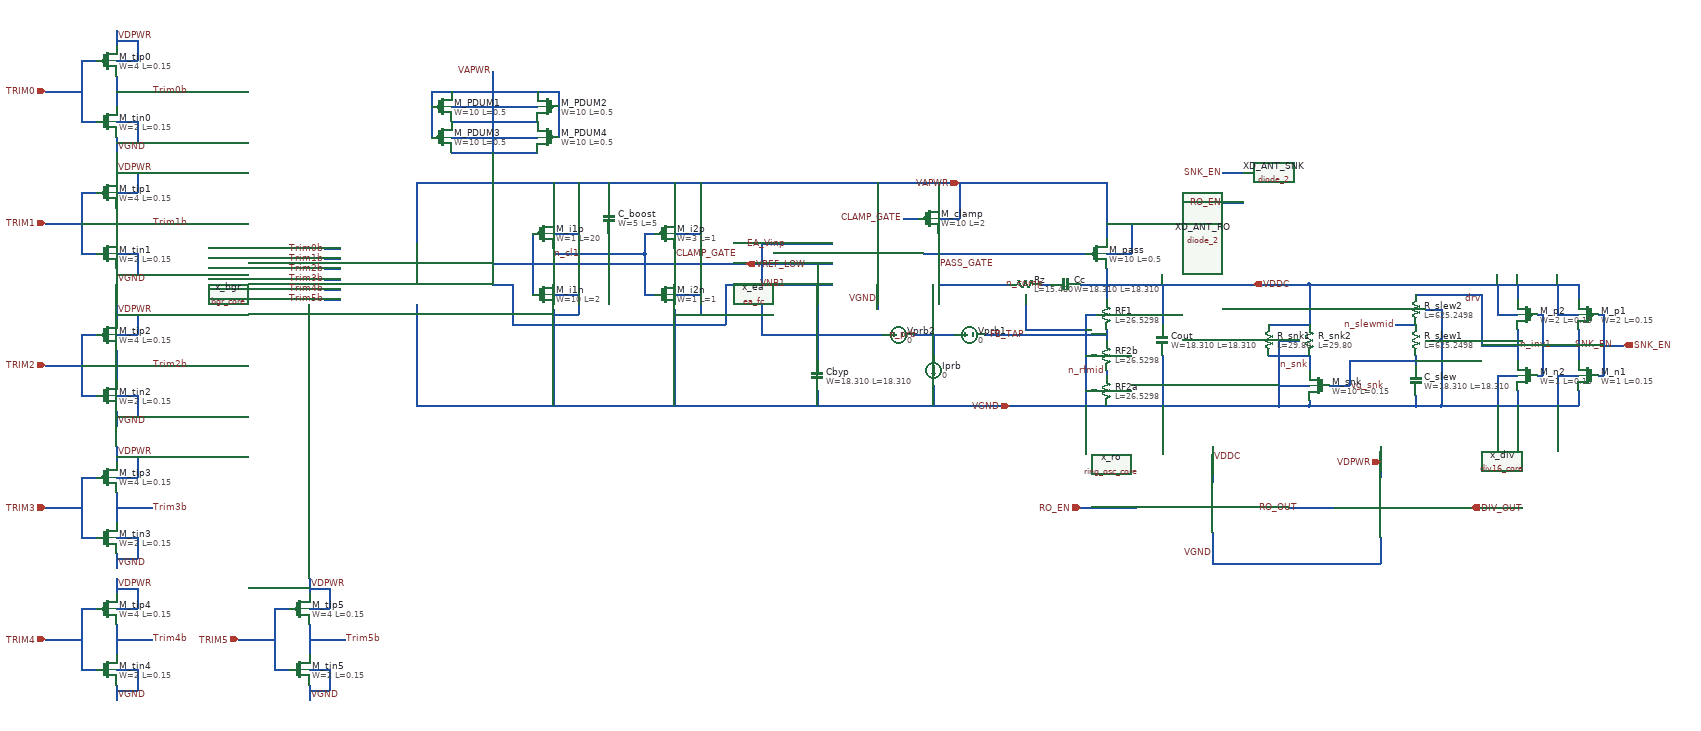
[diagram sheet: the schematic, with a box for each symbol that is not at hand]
v {xschem version=3.4.8RC file_version=1.3}
G {}
K {}
V {}
S {}
F {}
E {}
N 800 430 800 490 {lab=VGND}
N 950 380 1020 380 {lab=RO_OUT}
N 1020 380 1040 380 {lab=RO_OUT}
N 800 490 1040 490 {lab=VGND}
N -150 -260 590 -260 {lab=VAPWR}
N 590 -260 590 -150 {lab=VAPWR}
N 590 -120 640 -120 {lab=VAPWR}
N 640 -180 640 -120 {lab=VAPWR}
N 590 -180 640 -180 {lab=VAPWR}
N 590 -90 590 -30 {lab=VDDC}
N 590 180 790 180 {lab=VGND}
N 590 -60 800 -60 {lab=VDDC}
N 700 -60 700 20 {lab=VDDC}
N 700 80 700 180 {lab=VGND}
N -150 180 590 180 {lab=VGND}
N 350 -120 550 -120 {lab=PASS_GATE}
N 140 -260 140 -200 {lab=VAPWR}
N 790 180 800 180 {lab=VGND}
N 540 -60 590 -60 {lab=VDDC}
N 460 -60 480 -60 {lab=n_comp}
N 260 -60 280 -60 {lab=PASS_GATE}
N 260 -120 260 -60 {lab=PASS_GATE}
N 430 -40 430 30 {lab=VGND}
N 550 0 570 0 {lab=VGND}
N 550 0 550 110 {lab=VGND}
N 550 150 570 150 {lab=VGND}
N 550 110 550 180 {lab=VGND}
N 430 30 550 30 {lab=VGND}
N -770 -260 -770 -140 {lab=VAPWR}
N -770 -20 -770 180 {lab=VGND}
N 20 -100 20 90 {lab=VREF_LOW}
N 20 150 20 180 {lab=VGND}
N -160 -100 -120 -100 {lab=VREF_LOW}
N -160 -60 -120 -60 {lab=VNB1}
N 230 -120 350 -120 {lab=PASS_GATE}
N 280 -60 400 -60 {lab=PASS_GATE}
N -320 180 -150 180 {lab=VGND}
N -320 -260 -150 -260 {lab=VAPWR}
N -90 40 80 40 {lab=EA_Vinp}
N -120 -60 50 -60 {lab=VNB1}
N -120 -100 50 -100 {lab=VREF_LOW}
N 140 -40 140 -30 {lab=VGND}
N 990 80 990 110 {lab=n_snk}
N 990 170 990 180 {lab=VGND}
N 800 -60 990 -60 {lab=VDDC}
N 990 -60 990 20 {lab=VDDC}
N 930 50 970 50 {lab=VGND}
N 930 50 930 180 {lab=VGND}
N 930 180 990 180 {lab=VGND}
N 1030 140 1070 140 {lab=vg_snk}
N 800 180 930 180 {lab=VGND}
N 1200 80 1200 100 {lab=vg_snk}
N 1070 90 1070 140 {lab=vg_snk}
N 1070 90 1200 90 {lab=vg_snk}
N 1200 160 1200 180 {lab=VGND}
N 990 180 1200 180 {lab=VGND}
N 1220 50 1250 50 {lab=VGND}
N 1250 50 1250 180 {lab=VGND}
N 1200 180 1250 180 {lab=VGND}
N 1520 30 1520 90 {lab=n_inv1}
N 1520 150 1520 180 {lab=VGND}
N 1560 0 1570 0 {lab=SNK_EN}
N 1570 0 1570 120 {lab=SNK_EN}
N 1560 120 1570 120 {lab=SNK_EN}
N 1570 60 1610 60 {lab=SNK_EN}
N 1400 30 1400 90 {lab=drv}
N 1330 60 1400 60 {lab=drv}
N 1400 150 1400 180 {lab=VGND}
N 1250 180 1520 180 {lab=VGND}
N 1440 0 1450 0 {lab=n_inv1}
N 1450 0 1450 120 {lab=n_inv1}
N 1440 120 1450 120 {lab=n_inv1}
N 1450 60 1520 60 {lab=n_inv1}
N 1480 0 1520 0 {lab=VDDC}
N 1480 -50 1480 0 {lab=VDDC}
N 1360 0 1400 0 {lab=VDDC}
N 1360 -50 1360 0 {lab=VDDC}
N 1360 -60 1360 -50 {lab=VDDC}
N 1480 -60 1480 -50 {lab=VDDC}
N 1400 -60 1400 -30 {lab=VDDC}
N 1520 -60 1520 -30 {lab=VDDC}
N 990 -60 1520 -60 {lab=VDDC}
N 1330 -30 1330 60 {lab=drv}
N 1040 490 1130 490 {lab=VGND}
N 1130 440 1130 490 {lab=VGND}
N 800 260 800 330 {lab=VDDC}
N 1130 260 1130 320 {lab=VDPWR}
N 1220 380 1320 380 {lab=DIV_OUT}
N -90 -140 50 -140 {lab=EA_Vinp}
N -770 -260 -740 -260 {lab=VAPWR}
N -770 180 -740 180 {lab=VGND}
N 140 -30 140 -10 {lab=VGND}
N 540 380 650 380 {lab=RO_EN}
N 250 160 250 180 {lab=VGND}
N 350 40 400 40 {lab=FB_TAP}
N 930 140 990 140 {lab=VGND}
N 1360 120 1400 120 {lab=VGND}
N 1360 120 1360 180 {lab=VGND}
N 1480 120 1520 120 {lab=VGND}
N 1480 120 1480 180 {lab=VGND}
N -520 -100 -160 -100 {lab=VREF_LOW}
N -640 -260 -320 -260 {lab=VAPWR}
N -640 180 -320 180 {lab=VGND}
N -540 -160 -540 -100 {lab=VREF_LOW}
N -540 -100 -540 -40 {lab=VREF_LOW}
N -620 -60 -580 -60 {lab=VNB1}
N -580 -60 -580 20 {lab=VNB1}
N -480 20 -160 20 {lab=VNB1}
N -160 -60 -160 20 {lab=VNB1}
N -500 -260 -500 -190 {lab=VAPWR}
N -500 -160 -450 -160 {lab=VAPWR}
N -450 -260 -450 -160 {lab=VAPWR}
N -500 -130 -500 -70 {lab=n_cl1}
N -500 -10 -500 180 {lab=VGND}
N -500 -40 -450 -40 {lab=VGND}
N -450 -40 -450 0 {lab=VGND}
N -500 0 -450 0 {lab=VGND}
N -400 -120 -320 -120 {lab=n_cl1}
N -320 -160 -320 -120 {lab=n_cl1}
N -320 -160 -300 -160 {lab=n_cl1}
N -320 -120 -320 -40 {lab=n_cl1}
N -320 -40 -300 -40 {lab=n_cl1}
N -260 -10 -260 180 {lab=VGND}
N -260 0 -210 0 {lab=VGND}
N -210 -40 -210 0 {lab=VGND}
N -260 -40 -210 -40 {lab=VGND}
N -260 -130 -260 -70 {lab=CLAMP_GATE}
N -260 -260 -260 -190 {lab=VAPWR}
N -260 -160 -210 -160 {lab=VAPWR}
N -210 -260 -210 -160 {lab=VAPWR}
N 260 -160 260 -120 {lab=PASS_GATE}
N 260 -260 260 -220 {lab=VAPWR}
N 260 -190 300 -190 {lab=VAPWR}
N 300 -260 300 -190 {lab=VAPWR}
N 190 -190 220 -190 {lab=CLAMP_GATE}
N 80 40 150 40 {lab=EA_Vinp}
N 210 40 290 40 {lab=n_prb}
N 250 40 250 80 {lab=n_prb}
N -500 -120 -400 -120 {lab=n_cl1}
N -580 20 -480 20 {lab=VNB1}
N -620 -100 -520 -100 {lab=VREF_LOW}
N -740 -260 -640 -260 {lab=VAPWR}
N -740 180 -640 180 {lab=VGND}
N -390 -160 -390 -120 {lab=n_cl1}
N -390 -260 -390 -220 {lab=VAPWR}
N -1360 -470 -1360 -410 {lab=Trim0b}
N -1360 -440 -1290 -440 {lab=Trim0b}
N -1360 -350 -1360 -320 {lab=VGND}
N -1360 -500 -1320 -500 {lab=VDPWR}
N -1360 -560 -1360 -530 {lab=VDPWR}
N -1360 -380 -1320 -380 {lab=VGND}
N -1430 -500 -1400 -500 {lab=TRIM0}
N -1430 -500 -1430 -380 {lab=TRIM0}
N -1430 -380 -1400 -380 {lab=TRIM0}
N -1500 -440 -1430 -440 {lab=TRIM0}
N -1500 -180 -1430 -180 {lab=TRIM1}
N -1500 100 -1430 100 {lab=TRIM2}
N -1500 380 -1430 380 {lab=TRIM3}
N -950 -130 -920 -130 {lab=Trim0b}
N -950 -110 -920 -110 {lab=Trim1b}
N -950 -90 -920 -90 {lab=Trim2b}
N -950 -70 -920 -70 {lab=Trim3b}
N -1320 -540 -1320 -500 {lab=VDPWR}
N -1360 -540 -1320 -540 {lab=VDPWR}
N -1320 -380 -1320 -340 {lab=VGND}
N -1360 -340 -1320 -340 {lab=VGND}
N -1360 -210 -1360 -150 {lab=Trim1b}
N -1360 -90 -1360 -60 {lab=VGND}
N -1360 -240 -1320 -240 {lab=VDPWR}
N -1360 -300 -1360 -270 {lab=VDPWR}
N -1360 -120 -1320 -120 {lab=VGND}
N -1430 -240 -1400 -240 {lab=TRIM1}
N -1430 -240 -1430 -120 {lab=TRIM1}
N -1430 -120 -1400 -120 {lab=TRIM1}
N -1320 -280 -1320 -240 {lab=VDPWR}
N -1360 -280 -1320 -280 {lab=VDPWR}
N -1320 -120 -1320 -80 {lab=VGND}
N -1360 -80 -1320 -80 {lab=VGND}
N -1360 70 -1360 130 {lab=Trim2b}
N -1360 190 -1360 220 {lab=VGND}
N -1360 40 -1320 40 {lab=VDPWR}
N -1360 -20 -1360 10 {lab=VDPWR}
N -1360 160 -1320 160 {lab=VGND}
N -1430 40 -1400 40 {lab=TRIM2}
N -1430 40 -1430 160 {lab=TRIM2}
N -1430 160 -1400 160 {lab=TRIM2}
N -1320 0 -1320 40 {lab=VDPWR}
N -1360 0 -1320 0 {lab=VDPWR}
N -1320 160 -1320 200 {lab=VGND}
N -1360 200 -1320 200 {lab=VGND}
N -1360 350 -1360 410 {lab=Trim3b}
N -1360 470 -1360 500 {lab=VGND}
N -1360 320 -1320 320 {lab=VDPWR}
N -1360 260 -1360 290 {lab=VDPWR}
N -1360 440 -1320 440 {lab=VGND}
N -1430 320 -1400 320 {lab=TRIM3}
N -1430 320 -1430 440 {lab=TRIM3}
N -1430 440 -1400 440 {lab=TRIM3}
N -1320 280 -1320 320 {lab=VDPWR}
N -1360 280 -1320 280 {lab=VDPWR}
N -1320 440 -1320 480 {lab=VGND}
N -1360 480 -1320 480 {lab=VGND}
N -1360 380 -1290 380 {lab=Trim3b}
N -1360 100 -1290 100 {lab=Trim2b}
N -1360 -180 -1290 -180 {lab=Trim1b}
N 1220 -10 1250 -10 {lab=VGND}
N 1250 -10 1250 50 {lab=VGND}
N 1200 -40 1330 -40 {lab=drv}
N 1330 -40 1330 -30 {lab=drv}
N 1160 20 1200 20 {lab=n_slewmid}
N 590 110 590 120 {lab=n_rfmid}
N 550 80 570 80 {lab=VGND}
N 590 30 590 50 {lab=FB_TAP}
N 400 40 590 40 {lab=FB_TAP}
N -90 -140 -90 40 {lab=EA_Vinp}
N 250 140 250 160 {lab=VGND}
N 910 20 990 20 {lab=VDDC}
N 910 80 990 80 {lab=n_snk}
N -700 -320 -530 -320 {lab=VAPWR}
N -700 -350 -530 -350 {lab=VAPWR}
N -700 -380 -530 -380 {lab=VAPWR}
N -700 -410 -530 -410 {lab=VAPWR}
N -700 -440 -530 -440 {lab=VAPWR}
N -490 -410 -490 -350 {lab=VAPWR}
N -740 -410 -740 -350 {lab=VAPWR}
N -740 -440 -740 -410 {lab=VAPWR}
N -740 -440 -700 -440 {lab=VAPWR}
N -530 -440 -490 -440 {lab=VAPWR}
N -490 -440 -490 -410 {lab=VAPWR}
N -620 -350 -620 -320 {lab=VAPWR}
N -620 -380 -620 -350 {lab=VAPWR}
N -620 -410 -620 -380 {lab=VAPWR}
N -620 -440 -620 -410 {lab=VAPWR}
N -620 -480 -620 -440 {lab=VAPWR}
N 820 -280 860 -280 {lab=SNK_EN}
N 820 -220 860 -220 {lab=RO_EN}
N -950 -50 -920 -50 {lab=Trim5b}
N -950 -30 -920 -30 {lab=Trim5b}
N -1500 640 -1430 640 {lab=TRIM4}
N -1360 610 -1360 670 {lab=Trim4b}
N -1360 730 -1360 760 {lab=VGND}
N -1360 580 -1320 580 {lab=VDPWR}
N -1360 520 -1360 550 {lab=VDPWR}
N -1360 700 -1320 700 {lab=VGND}
N -1430 580 -1400 580 {lab=TRIM4}
N -1430 580 -1430 700 {lab=TRIM4}
N -1430 700 -1400 700 {lab=TRIM4}
N -1320 540 -1320 580 {lab=VDPWR}
N -1360 540 -1320 540 {lab=VDPWR}
N -1320 700 -1320 740 {lab=VGND}
N -1360 740 -1320 740 {lab=VGND}
N -1360 640 -1290 640 {lab=Trim4b}
N -1120 640 -1050 640 {lab=TRIM5}
N -980 610 -980 670 {lab=Trim5b}
N -980 730 -980 760 {lab=VGND}
N -980 580 -940 580 {lab=VDPWR}
N -980 520 -980 550 {lab=VDPWR}
N -980 700 -940 700 {lab=VGND}
N -1050 580 -1020 580 {lab=TRIM5}
N -1050 580 -1050 700 {lab=TRIM5}
N -1050 700 -1020 700 {lab=TRIM5}
N -940 540 -940 580 {lab=VDPWR}
N -980 540 -940 540 {lab=VDPWR}
N -940 700 -940 740 {lab=VGND}
N -980 740 -940 740 {lab=VGND}
N -980 640 -910 640 {lab=Trim5b}
C {ring_osc_core.sym} 800 380 0 0 {name=x_ro}
C {lab_pin.sym} 970 380 3 0 {name=p9 sig_type=std_logic lab=RO_OUT}
C {lab_pin.sym} 800 280 2 0 {name=p10 sig_type=std_logic lab=VDDC


}
C {pfet_g5v0d10v5.sym} 570 -120 0 0 {name=M_pass
W=10
L=0.5
nf=1
mult=40
ad="expr('int((@nf + 1)/2) * @W / @nf * 0.29')"
pd="expr('2*int((@nf + 1)/2) * (@W / @nf + 0.29)')"
as="expr('int((@nf + 2)/2) * @W / @nf * 0.29')"
ps="expr('2*int((@nf + 2)/2) * (@W / @nf + 0.29)')"
nrd="expr('0.29 / @W ')" nrs="expr('0.29 / @W ')"
sa=0 sb=0 sd=0
model=pfet_g5v0d10v5
spiceprefix=X
}
C {ea_fc.sym} 130 -120 0 0 {name=x_ea}
C {res_high_po_0p69.sym} 590 0 0 0 {name=RF1
L=26.5298
model=res_high_po_0p69
spiceprefix=X
mult=1}
C {res_high_po_0p69.sym} 590 150 0 0 {name=RF2a
L=26.5298
model=res_high_po_0p69
spiceprefix=X
mult=1}
C {res_high_po_0p69.sym} 430 -60 1 1 {name=Rz
L=15.480
model=res_high_po_0p69
spiceprefix=X
mult=1}
C {cap_mim_m3_1.sym} 700 50 0 0 {name=Cout model=cap_mim_m3_1 W=18.310 L=18.310 MF=32 spiceprefix=X}
C {cap_mim_m3_1.sym} 510 -60 3 0 {name=Cc model=cap_mim_m3_1 W=18.310 L=18.310 MF=4 spiceprefix=X}
C {bgr_core.sym} -770 -80 0 0 {name=x_bgr}
C {lab_pin.sym} -40 -60 3 0 {name=p4 sig_type=std_logic lab=VNB1


}
C {cap_mim_m3_1.sym} 20 120 0 0 {name=Cbyp model=cap_mim_m3_1 W=18.310 L=18.310 MF=3 spiceprefix=X}
C {res_high_po_0p69.sym} 1200 -10 0 1 {name=R_slew2
L=625.2498
model=res_high_po_0p69
spiceprefix=X
mult=1}
C {cap_mim_m3_1.sym} 1200 130 0 0 {name=C_slew model=cap_mim_m3_1 W=18.310 L=18.310 MF=2 spiceprefix=X}
C {lab_pin.sym} 1070 140 2 0 {name=p2 sig_type=std_logic lab=vg_snk


}
C {lab_pin.sym} 1330 -30 2 1 {name=p3 sig_type=std_logic lab=drv


}
C {pfet_01v8.sym} 1540 0 0 1 {name=M_p1
W=2
L=0.15
nf=1
mult=1
ad="expr('int((@nf + 1)/2) * @W / @nf * 0.29')"
pd="expr('2*int((@nf + 1)/2) * (@W / @nf + 0.29)')"
as="expr('int((@nf + 2)/2) * @W / @nf * 0.29')"
ps="expr('2*int((@nf + 2)/2) * (@W / @nf + 0.29)')"
nrd="expr('0.29 / @W ')" nrs="expr('0.29 / @W ')"
sa=0 sb=0 sd=0
model=pfet_01v8
spiceprefix=X
}
C {pfet_01v8.sym} 1420 0 0 1 {name=M_p2
W=2
L=0.15
nf=1
mult=1
ad="expr('int((@nf + 1)/2) * @W / @nf * 0.29')"
pd="expr('2*int((@nf + 1)/2) * (@W / @nf + 0.29)')"
as="expr('int((@nf + 2)/2) * @W / @nf * 0.29')"
ps="expr('2*int((@nf + 2)/2) * (@W / @nf + 0.29)')"
nrd="expr('0.29 / @W ')" nrs="expr('0.29 / @W ')"
sa=0 sb=0 sd=0
model=pfet_01v8
spiceprefix=X
}
C {lab_pin.sym} 1590 60 1 1 {name=p5 sig_type=std_logic lab=SNK_EN


}
C {lab_pin.sym} 1470 60 1 1 {name=p6 sig_type=std_logic lab=n_inv1


}
C {res_high_po_5p73.sym} 990 50 0 0 {name=R_snk2
L=29.80
model=res_high_po_5p73
spiceprefix=X
mult=1}
C {div16_core.sym} 1130 380 0 0 {name=x_div}
C {ipin.sym} 1610 60 0 1 {name=p13 lab=SNK_EN}
C {ipin.sym} -1500 -440 0 0 {name=p14 lab=TRIM0}
C {ipin.sym} -1500 -180 0 0 {name=p16 lab=TRIM1}
C {ipin.sym} -1500 100 0 0 {name=p17 lab=TRIM2}
C {ipin.sym} -1500 380 0 0 {name=p18 lab=TRIM3}
C {lab_pin.sym} 140 -30 0 0 {name=p19 sig_type=std_logic lab=VGND


}
C {lab_pin.sym} 800 470 0 0 {name=p20 sig_type=std_logic lab=VGND


}
C {iopin.sym} 1130 290 0 0 {name=p21 lab=VDPWR}
C {iopin.sym} 400 180 0 0 {name=p7 lab=VGND}
C {iopin.sym} 300 -260 0 0 {name=p15 lab=VAPWR}
C {ipin.sym} 540 380 0 0 {name=p8 lab=RO_EN}
C {vsource.sym} 320 40 3 0 {name=Vprb1 value=0 savecurrent=false}
C {vsource.sym} 180 40 3 0 {name=Vprb2 value=0 savecurrent=false}
C {isource.sym} 250 110 0 0 {name=Iprb value=0}
C {opin.sym} 1310 380 0 0 {name=p11 lab=DIV_OUT}
C {opin.sym} -120 -100 3 0 {name=p12 lab=VREF_LOW}
C {opin.sym} 880 -60 3 0 {name=p1 lab=VDDC}
C {pfet_g5v0d10v5.sym} -520 -160 0 0 {name=M_i1p
W=1
L=20
nf=1
mult=1
ad="expr('int((@nf + 1)/2) * @W / @nf * 0.29')"
pd="expr('2*int((@nf + 1)/2) * (@W / @nf + 0.29)')"
as="expr('int((@nf + 2)/2) * @W / @nf * 0.29')"
ps="expr('2*int((@nf + 2)/2) * (@W / @nf + 0.29)')"
nrd="expr('0.29 / @W ')" nrs="expr('0.29 / @W ')"
sa=0 sb=0 sd=0
model=pfet_g5v0d10v5
spiceprefix=X
}
C {nfet_01v8.sym} 1010 140 0 1 {name=M_snk
W=10
L=0.15
nf=1 
mult=4
ad="expr('int((@nf + 1)/2) * @W / @nf * 0.29')"
pd="expr('2*int((@nf + 1)/2) * (@W / @nf + 0.29)')"
as="expr('int((@nf + 2)/2) * @W / @nf * 0.29')"
ps="expr('2*int((@nf + 2)/2) * (@W / @nf + 0.29)')"
nrd="expr('0.29 / @W ')" nrs="expr('0.29 / @W ')"
sa=0 sb=0 sd=0
model=nfet_01v8
spiceprefix=X
}
C {nfet_01v8.sym} 1420 120 0 1 {name=M_n2
W=1
L=0.15
nf=1 
mult=1
ad="expr('int((@nf + 1)/2) * @W / @nf * 0.29')"
pd="expr('2*int((@nf + 1)/2) * (@W / @nf + 0.29)')"
as="expr('int((@nf + 2)/2) * @W / @nf * 0.29')"
ps="expr('2*int((@nf + 2)/2) * (@W / @nf + 0.29)')"
nrd="expr('0.29 / @W ')" nrs="expr('0.29 / @W ')"
sa=0 sb=0 sd=0
model=nfet_01v8
spiceprefix=X
}
C {nfet_01v8.sym} 1540 120 0 1 {name=M_n1
W=1
L=0.15
nf=1 
mult=1
ad="expr('int((@nf + 1)/2) * @W / @nf * 0.29')"
pd="expr('2*int((@nf + 1)/2) * (@W / @nf + 0.29)')"
as="expr('int((@nf + 2)/2) * @W / @nf * 0.29')"
ps="expr('2*int((@nf + 2)/2) * (@W / @nf + 0.29)')"
nrd="expr('0.29 / @W ')" nrs="expr('0.29 / @W ')"
sa=0 sb=0 sd=0
model=nfet_01v8
spiceprefix=X
}
C {nfet_g5v0d10v5.sym} -520 -40 0 0 {name=M_i1n
W=10
L=2
nf=1
mult=1
ad="expr('int((@nf + 1)/2) * @W / @nf * 0.29')"
pd="expr('2*int((@nf + 1)/2) * (@W / @nf + 0.29)')"
as="expr('int((@nf + 2)/2) * @W / @nf * 0.29')"
ps="expr('2*int((@nf + 2)/2) * (@W / @nf + 0.29)')"
nrd="expr('0.29 / @W ')" nrs="expr('0.29 / @W ')"
sa=0 sb=0 sd=0
model=nfet_g5v0d10v5
spiceprefix=X
}
C {lab_pin.sym} -500 -120 2 0 {name=p22 sig_type=std_logic lab=n_cl1


}
C {nfet_g5v0d10v5.sym} -280 -40 0 0 {name=M_i2n
W=1
L=1
nf=1
mult=1
ad="expr('int((@nf + 1)/2) * @W / @nf * 0.29')"
pd="expr('2*int((@nf + 1)/2) * (@W / @nf + 0.29)')"
as="expr('int((@nf + 2)/2) * @W / @nf * 0.29')"
ps="expr('2*int((@nf + 2)/2) * (@W / @nf + 0.29)')"
nrd="expr('0.29 / @W ')" nrs="expr('0.29 / @W ')"
sa=0 sb=0 sd=0
model=nfet_g5v0d10v5
spiceprefix=X
}
C {pfet_g5v0d10v5.sym} -280 -160 0 0 {name=M_i2p
W=3
L=1
nf=1
mult=1
ad="expr('int((@nf + 1)/2) * @W / @nf * 0.29')"
pd="expr('2*int((@nf + 1)/2) * (@W / @nf + 0.29)')"
as="expr('int((@nf + 2)/2) * @W / @nf * 0.29')"
ps="expr('2*int((@nf + 2)/2) * (@W / @nf + 0.29)')"
nrd="expr('0.29 / @W ')" nrs="expr('0.29 / @W ')"
sa=0 sb=0 sd=0
model=pfet_g5v0d10v5
spiceprefix=X
}
C {pfet_g5v0d10v5.sym} 240 -190 0 0 {name=M_clamp
W=10
L=2
nf=1
mult=1
ad="expr('int((@nf + 1)/2) * @W / @nf * 0.29')"
pd="expr('2*int((@nf + 1)/2) * (@W / @nf + 0.29)')"
as="expr('int((@nf + 2)/2) * @W / @nf * 0.29')"
ps="expr('2*int((@nf + 2)/2) * (@W / @nf + 0.29)')"
nrd="expr('0.29 / @W ')" nrs="expr('0.29 / @W ')"
sa=0 sb=0 sd=0
model=pfet_g5v0d10v5
spiceprefix=X
}
C {lab_pin.sym} -260 -120 2 0 {name=p23 sig_type=std_logic lab=CLAMP_GATE


}
C {lab_pin.sym} 260 -100 2 0 {name=p24 sig_type=std_logic lab=PASS_GATE


}
C {lab_pin.sym} 190 -190 3 1 {name=p25 sig_type=std_logic lab=CLAMP_GATE


}
C {lab_pin.sym} -40 -140 1 0 {name=p26 sig_type=std_logic lab=EA_Vinp


}
C {cap_mim_m3_1.sym} -390 -190 2 0 {name=C_boost model=cap_mim_m3_1 W=5 L=5 MF=1 spiceprefix=X}
C {pfet_01v8.sym} -1380 -500 0 0 {name=M_tip0
W=4
L=0.15
nf=1
mult=1
ad="expr('int((@nf + 1)/2) * @W / @nf * 0.29')"
pd="expr('2*int((@nf + 1)/2) * (@W / @nf + 0.29)')"
as="expr('int((@nf + 2)/2) * @W / @nf * 0.29')"
ps="expr('2*int((@nf + 2)/2) * (@W / @nf + 0.29)')"
nrd="expr('0.29 / @W ')" nrs="expr('0.29 / @W ')"
sa=0 sb=0 sd=0
model=pfet_01v8
spiceprefix=X
}
C {nfet_01v8.sym} -1380 -380 0 0 {name=M_tin0
W=2
L=0.15
nf=1 
mult=1
ad="expr('int((@nf + 1)/2) * @W / @nf * 0.29')"
pd="expr('2*int((@nf + 1)/2) * (@W / @nf + 0.29)')"
as="expr('int((@nf + 2)/2) * @W / @nf * 0.29')"
ps="expr('2*int((@nf + 2)/2) * (@W / @nf + 0.29)')"
nrd="expr('0.29 / @W ')" nrs="expr('0.29 / @W ')"
sa=0 sb=0 sd=0
model=nfet_01v8
spiceprefix=X
}
C {lab_pin.sym} -1290 -440 2 0 {name=p27 sig_type=std_logic lab=Trim0b


}
C {lab_pin.sym} -1360 -550 2 0 {name=p28 sig_type=std_logic lab=VDPWR


}
C {lab_pin.sym} -1360 -330 2 0 {name=p29 sig_type=std_logic lab=VGND


}
C {lab_pin.sym} -1290 -180 2 0 {name=p36 sig_type=std_logic lab=Trim1b


}
C {lab_pin.sym} -1290 100 2 0 {name=p37 sig_type=std_logic lab=Trim2b


}
C {lab_pin.sym} -1290 380 2 0 {name=p38 sig_type=std_logic lab=Trim3b


}
C {lab_pin.sym} -950 -110 2 1 {name=p39 sig_type=std_logic lab=Trim1b


}
C {lab_pin.sym} -950 -130 2 1 {name=p40 sig_type=std_logic lab=Trim0b


}
C {lab_pin.sym} -950 -90 2 1 {name=p41 sig_type=std_logic lab=Trim2b


}
C {lab_pin.sym} -950 -70 2 1 {name=p42 sig_type=std_logic lab=Trim3b


}
C {pfet_01v8.sym} -1380 -240 0 0 {name=M_tip1
W=4
L=0.15
nf=1
mult=1
ad="expr('int((@nf + 1)/2) * @W / @nf * 0.29')"
pd="expr('2*int((@nf + 1)/2) * (@W / @nf + 0.29)')"
as="expr('int((@nf + 2)/2) * @W / @nf * 0.29')"
ps="expr('2*int((@nf + 2)/2) * (@W / @nf + 0.29)')"
nrd="expr('0.29 / @W ')" nrs="expr('0.29 / @W ')"
sa=0 sb=0 sd=0
model=pfet_01v8
spiceprefix=X
}
C {nfet_01v8.sym} -1380 -120 0 0 {name=M_tin1
W=2
L=0.15
nf=1 
mult=1
ad="expr('int((@nf + 1)/2) * @W / @nf * 0.29')"
pd="expr('2*int((@nf + 1)/2) * (@W / @nf + 0.29)')"
as="expr('int((@nf + 2)/2) * @W / @nf * 0.29')"
ps="expr('2*int((@nf + 2)/2) * (@W / @nf + 0.29)')"
nrd="expr('0.29 / @W ')" nrs="expr('0.29 / @W ')"
sa=0 sb=0 sd=0
model=nfet_01v8
spiceprefix=X
}
C {lab_pin.sym} -1360 -290 2 0 {name=p30 sig_type=std_logic lab=VDPWR


}
C {lab_pin.sym} -1360 -70 2 0 {name=p31 sig_type=std_logic lab=VGND


}
C {pfet_01v8.sym} -1380 40 0 0 {name=M_tip2
W=4
L=0.15
nf=1
mult=1
ad="expr('int((@nf + 1)/2) * @W / @nf * 0.29')"
pd="expr('2*int((@nf + 1)/2) * (@W / @nf + 0.29)')"
as="expr('int((@nf + 2)/2) * @W / @nf * 0.29')"
ps="expr('2*int((@nf + 2)/2) * (@W / @nf + 0.29)')"
nrd="expr('0.29 / @W ')" nrs="expr('0.29 / @W ')"
sa=0 sb=0 sd=0
model=pfet_01v8
spiceprefix=X
}
C {nfet_01v8.sym} -1380 160 0 0 {name=M_tin2
W=2
L=0.15
nf=1 
mult=1
ad="expr('int((@nf + 1)/2) * @W / @nf * 0.29')"
pd="expr('2*int((@nf + 1)/2) * (@W / @nf + 0.29)')"
as="expr('int((@nf + 2)/2) * @W / @nf * 0.29')"
ps="expr('2*int((@nf + 2)/2) * (@W / @nf + 0.29)')"
nrd="expr('0.29 / @W ')" nrs="expr('0.29 / @W ')"
sa=0 sb=0 sd=0
model=nfet_01v8
spiceprefix=X
}
C {lab_pin.sym} -1360 -10 2 0 {name=p32 sig_type=std_logic lab=VDPWR


}
C {lab_pin.sym} -1360 210 2 0 {name=p33 sig_type=std_logic lab=VGND


}
C {pfet_01v8.sym} -1380 320 0 0 {name=M_tip3
W=4
L=0.15
nf=1
mult=1
ad="expr('int((@nf + 1)/2) * @W / @nf * 0.29')"
pd="expr('2*int((@nf + 1)/2) * (@W / @nf + 0.29)')"
as="expr('int((@nf + 2)/2) * @W / @nf * 0.29')"
ps="expr('2*int((@nf + 2)/2) * (@W / @nf + 0.29)')"
nrd="expr('0.29 / @W ')" nrs="expr('0.29 / @W ')"
sa=0 sb=0 sd=0
model=pfet_01v8
spiceprefix=X
}
C {nfet_01v8.sym} -1380 440 0 0 {name=M_tin3
W=2
L=0.15
nf=1 
mult=1
ad="expr('int((@nf + 1)/2) * @W / @nf * 0.29')"
pd="expr('2*int((@nf + 1)/2) * (@W / @nf + 0.29)')"
as="expr('int((@nf + 2)/2) * @W / @nf * 0.29')"
ps="expr('2*int((@nf + 2)/2) * (@W / @nf + 0.29)')"
nrd="expr('0.29 / @W ')" nrs="expr('0.29 / @W ')"
sa=0 sb=0 sd=0
model=nfet_01v8
spiceprefix=X
}
C {lab_pin.sym} -1360 270 2 0 {name=p34 sig_type=std_logic lab=VDPWR


}
C {lab_pin.sym} -1360 490 2 0 {name=p35 sig_type=std_logic lab=VGND


}
C {res_high_po_0p69.sym} 1200 50 0 1 {name=R_slew1
L=625.2498
model=res_high_po_0p69
spiceprefix=X
mult=1}
C {lab_pin.sym} 1160 20 2 1 {name=p43 sig_type=std_logic lab=n_slewmid


}
C {res_high_po_0p69.sym} 590 80 0 0 {name=RF2b
L=26.5298
model=res_high_po_0p69
spiceprefix=X
mult=1}
C {lab_pin.sym} 590 110 0 0 {name=p44 sig_type=std_logic lab=n_rfmid


}
C {lab_pin.sym} 470 -60 3 0 {name=p45 sig_type=std_logic lab=n_comp


}
C {lab_pin.sym} 990 100 2 1 {name=p46 sig_type=std_logic lab=n_snk


}
C {lab_pin.sym} 430 40 1 1 {name=p47 sig_type=std_logic lab=FB_TAP


}
C {lab_pin.sym} 220 40 1 1 {name=p48 sig_type=std_logic lab=n_prb


}
C {res_high_po_5p73.sym} 910 50 0 1 {name=R_snk1
L=29.80
model=res_high_po_5p73
spiceprefix=X
mult=1}
C {pfet_g5v0d10v5.sym} -720 -410 0 0 {name=M_PDUM1
W=10
L=0.5
nf=1
mult=1
ad="expr('int((@nf + 1)/2) * @W / @nf * 0.29')"
pd="expr('2*int((@nf + 1)/2) * (@W / @nf + 0.29)')"
as="expr('int((@nf + 2)/2) * @W / @nf * 0.29')"
ps="expr('2*int((@nf + 2)/2) * (@W / @nf + 0.29)')"
nrd="expr('0.29 / @W ')" nrs="expr('0.29 / @W ')"
sa=0 sb=0 sd=0
model=pfet_g5v0d10v5
spiceprefix=X
}
C {pfet_g5v0d10v5.sym} -510 -410 0 1 {name=M_PDUM2
W=10
L=0.5
nf=1
mult=1
ad="expr('int((@nf + 1)/2) * @W / @nf * 0.29')"
pd="expr('2*int((@nf + 1)/2) * (@W / @nf + 0.29)')"
as="expr('int((@nf + 2)/2) * @W / @nf * 0.29')"
ps="expr('2*int((@nf + 2)/2) * (@W / @nf + 0.29)')"
nrd="expr('0.29 / @W ')" nrs="expr('0.29 / @W ')"
sa=0 sb=0 sd=0
model=pfet_g5v0d10v5
spiceprefix=X
}
C {pfet_g5v0d10v5.sym} -720 -350 0 0 {name=M_PDUM3
W=10
L=0.5
nf=1
mult=1
ad="expr('int((@nf + 1)/2) * @W / @nf * 0.29')"
pd="expr('2*int((@nf + 1)/2) * (@W / @nf + 0.29)')"
as="expr('int((@nf + 2)/2) * @W / @nf * 0.29')"
ps="expr('2*int((@nf + 2)/2) * (@W / @nf + 0.29)')"
nrd="expr('0.29 / @W ')" nrs="expr('0.29 / @W ')"
sa=0 sb=0 sd=0
model=pfet_g5v0d10v5
spiceprefix=X
}
C {pfet_g5v0d10v5.sym} -510 -350 0 1 {name=M_PDUM4
W=10
L=0.5
nf=1
mult=1
ad="expr('int((@nf + 1)/2) * @W / @nf * 0.29')"
pd="expr('2*int((@nf + 1)/2) * (@W / @nf + 0.29)')"
as="expr('int((@nf + 2)/2) * @W / @nf * 0.29')"
ps="expr('2*int((@nf + 2)/2) * (@W / @nf + 0.29)')"
nrd="expr('0.29 / @W ')" nrs="expr('0.29 / @W ')"
sa=0 sb=0 sd=0
model=pfet_g5v0d10v5
spiceprefix=X
}
C {lab_pin.sym} -620 -480 1 0 {name=p49 sig_type=std_logic lab=VAPWR


}
C {diode_2.sym} 950 -280 0 0 {name=XD_ANT_SNK VGND=VGND VNB=VGND VPB=VDPWR VPWR=VDPWR prefix=sky130_fd_sc_hd__ }
C {diode_2.sym} 950 -220 0 0 {name=XD_ANT_RO VGND=VGND VNB=VGND VPB=VDPWR VPWR=VDPWR prefix=sky130_fd_sc_hd__ }
C {lab_pin.sym} 820 -280 2 1 {name=p50 sig_type=std_logic lab=SNK_EN



}
C {lab_pin.sym} 820 -220 2 1 {name=p51 sig_type=std_logic lab=RO_EN



}
C {lab_pin.sym} -950 -50 2 1 {name=p52 sig_type=std_logic lab=Trim4b


}
C {lab_pin.sym} -950 -30 2 1 {name=p53 sig_type=std_logic lab=Trim5b


}
C {ipin.sym} -1500 640 0 0 {name=p54 lab=TRIM4
}
C {lab_pin.sym} -1290 640 2 0 {name=p55 sig_type=std_logic lab=Trim4b


}
C {pfet_01v8.sym} -1380 580 0 0 {name=M_tip4
W=4
L=0.15
nf=1
mult=1
ad="expr('int((@nf + 1)/2) * @W / @nf * 0.29')"
pd="expr('2*int((@nf + 1)/2) * (@W / @nf + 0.29)')"
as="expr('int((@nf + 2)/2) * @W / @nf * 0.29')"
ps="expr('2*int((@nf + 2)/2) * (@W / @nf + 0.29)')"
nrd="expr('0.29 / @W ')" nrs="expr('0.29 / @W ')"
sa=0 sb=0 sd=0
model=pfet_01v8
spiceprefix=X
}
C {nfet_01v8.sym} -1380 700 0 0 {name=M_tin4
W=2
L=0.15
nf=1 
mult=1
ad="expr('int((@nf + 1)/2) * @W / @nf * 0.29')"
pd="expr('2*int((@nf + 1)/2) * (@W / @nf + 0.29)')"
as="expr('int((@nf + 2)/2) * @W / @nf * 0.29')"
ps="expr('2*int((@nf + 2)/2) * (@W / @nf + 0.29)')"
nrd="expr('0.29 / @W ')" nrs="expr('0.29 / @W ')"
sa=0 sb=0 sd=0
model=nfet_01v8
spiceprefix=X
}
C {lab_pin.sym} -1360 530 2 0 {name=p56 sig_type=std_logic lab=VDPWR


}
C {lab_pin.sym} -1360 750 2 0 {name=p57 sig_type=std_logic lab=VGND


}
C {ipin.sym} -1120 640 0 0 {name=p58 lab=TRIM5
}
C {lab_pin.sym} -910 640 2 0 {name=p59 sig_type=std_logic lab=Trim5b


}
C {pfet_01v8.sym} -1000 580 0 0 {name=M_tip5
W=4
L=0.15
nf=1
mult=1
ad="expr('int((@nf + 1)/2) * @W / @nf * 0.29')"
pd="expr('2*int((@nf + 1)/2) * (@W / @nf + 0.29)')"
as="expr('int((@nf + 2)/2) * @W / @nf * 0.29')"
ps="expr('2*int((@nf + 2)/2) * (@W / @nf + 0.29)')"
nrd="expr('0.29 / @W ')" nrs="expr('0.29 / @W ')"
sa=0 sb=0 sd=0
model=pfet_01v8
spiceprefix=X
}
C {nfet_01v8.sym} -1000 700 0 0 {name=M_tin5
W=2
L=0.15
nf=1 
mult=1
ad="expr('int((@nf + 1)/2) * @W / @nf * 0.29')"
pd="expr('2*int((@nf + 1)/2) * (@W / @nf + 0.29)')"
as="expr('int((@nf + 2)/2) * @W / @nf * 0.29')"
ps="expr('2*int((@nf + 2)/2) * (@W / @nf + 0.29)')"
nrd="expr('0.29 / @W ')" nrs="expr('0.29 / @W ')"
sa=0 sb=0 sd=0
model=nfet_01v8
spiceprefix=X
}
C {lab_pin.sym} -980 530 2 0 {name=p60 sig_type=std_logic lab=VDPWR


}
C {lab_pin.sym} -980 750 2 0 {name=p61 sig_type=std_logic lab=VGND


}
